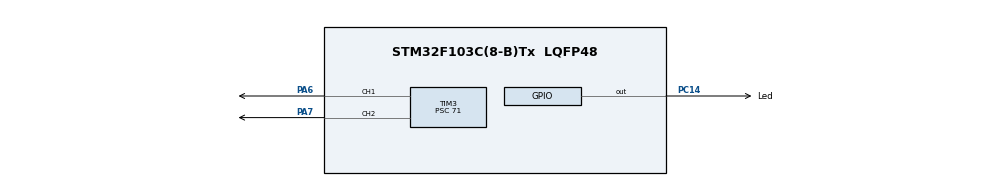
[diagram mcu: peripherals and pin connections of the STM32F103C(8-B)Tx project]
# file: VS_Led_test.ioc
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Mcu.Family=STM32F1
Mcu.Name=STM32F103C(8-B)Tx
Mcu.Package=LQFP48
NVIC.PriorityGroup=NVIC_PRIORITYGROUP_4
PA13.Mode=Serial_Wire
PA13.Signal=SYS_JTMS-SWDIO
PA14.Mode=Serial_Wire
PA14.Signal=SYS_JTCK-SWCLK
PA6.Signal=S_TIM3_CH1
PA7.Signal=S_TIM3_CH2
PC14-OSC32_IN.GPIO_Label=Led
PC14-OSC32_IN.PinState=GPIO_PIN_SET
PC14-OSC32_IN.Signal=GPIO_Output
PD0-OSC_IN.Mode=HSE-External-Oscillator
PD0-OSC_IN.Signal=RCC_OSC_IN
PD1-OSC_OUT.Mode=HSE-External-Oscillator
PD1-OSC_OUT.Signal=RCC_OSC_OUT
ProjectManager.HeapSize=0x200
ProjectManager.StackSize=0x400
ProjectManager.TargetToolchain=CMake
RCC.APB1Freq_Value=8000000
RCC.APB2Freq_Value=8000000
SH.S_TIM3_CH1.0=TIM3_CH1,PWM Generation1 CH1
SH.S_TIM3_CH2.0=TIM3_CH2,PWM Generation2 CH2
TIM3.AutoReloadPreload=TIM_AUTORELOAD_PRELOAD_ENABLE
TIM3.Channel-PWM\ Generation1\ CH1=TIM_CHANNEL_1
TIM3.Channel-PWM\ Generation2\ CH2=TIM_CHANNEL_2
TIM3.Period=999
TIM3.Prescaler=71
VP_TIM3_VS_ClockSourceINT.Mode=Internal
board=custom

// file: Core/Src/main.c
/* USER CODE BEGIN Header */
/**
  ******************************************************************************
  * @file           : main.c
  * @brief          : Main program body
  ******************************************************************************
  * @attention
  *
  * Copyright (c) 2026 STMicroelectronics.
  * All rights reserved.
  *
  * This software is licensed under terms that can be found in the LICENSE file
  * in the root directory of this software component.
  * If no LICENSE file comes with this software, it is provided AS-IS.
  *
  ******************************************************************************
  */
/* USER CODE END Header */
#include "main.h"

/* USER CODE BEGIN Includes */
#include "Trace.h"
#include "Motor.h"
#include "PID.h"
/* USER CODE END Includes */

/* USER CODE BEGIN PD */
#define TRACE_LOST_STOP_MS   500U
#define SEARCH_RAMP_MS       150U
#define STARTUP_SETTLE_MS    200U

/* USER CODE END PD */

TIM_HandleTypeDef htim3;

/* USER CODE BEGIN PV */
static uint32_t trace_lost_since = 0U;
static uint8_t startup_done = 0U;

/* USER CODE END PV */

void SystemClock_Config(void);
static void MX_GPIO_Init(void);
static void MX_TIM3_Init(void);

/* USER CODE BEGIN 0 */
static float absf_local(float value)
{
  return (value < 0.0f) ? -value : value;
}

static int16_t clamp_i16(int16_t value, int16_t min_value, int16_t max_value)
{
  if (value < min_value)
  {
    return min_value;
  }
  if (value > max_value)
  {
    return max_value;
  }
  return value;
}

/* USER CODE END 0 */

int main(void)
{

  /* MCU Configuration--------------------------------------------------------*/

  /* Reset of all peripherals, Initializes the Flash interface and the Systick. */
  HAL_Init();

  /* Configure the system clock */
  SystemClock_Config();

  /* Initialize all configured peripherals */
  MX_GPIO_Init();
  MX_TIM3_Init();
  /* USER CODE BEGIN 2 */

  HAL_TIM_PWM_Start(&htim3, TIM_CHANNEL_1);
  HAL_TIM_PWM_Start(&htim3, TIM_CHANNEL_2);

  // 启动稳定期：让传感器滤波器建立稳态
  {
    uint32_t settle_start = HAL_GetTick();
    while ((HAL_GetTick() - settle_start) < STARTUP_SETTLE_MS) {
      trace_get_error();
      HAL_Delay(10);
    }
    startup_done = 1U;
    pid_reset();
  }

  /* USER CODE END 2 */

  /* Infinite loop */
  /* USER CODE BEGIN WHILE */
  while (1)
  {
    float error = trace_get_error();
    const TraceState *trace = trace_get_state();
    uint8_t line_lost = trace->line_lost;

    if (line_lost)
    {
      float last_err = trace_get_last_error();
      uint32_t now = HAL_GetTick();

      if (trace_lost_since == 0U)
      {
        trace_lost_since = now;
      }

      uint32_t lost_duration = now - trace_lost_since;

      if (lost_duration >= TRACE_LOST_STOP_MS)
      {
        motor_stop();
        pid_reset();
        HAL_Delay(10);
        continue;
      }

      // 渐进式搜索：速度随丢线时间增加
      int16_t search_spd = (int16_t)(SEARCH_SPEED / 2);
      if (lost_duration > SEARCH_RAMP_MS)
      {
        search_spd = SEARCH_SPEED;
      }

      if (last_err >= 0.0f)
      {
        motor_set(search_spd, -search_spd);
      }
      else
      {
        motor_set(-search_spd, search_spd);
      }
      HAL_Delay(10);
      continue;
    }

    trace_lost_since = 0U;
    calc_pid(error, line_lost);

    float abs_error = absf_local(error);
    int16_t base_speed = (int16_t)(BASE_SPEED - (int16_t)(abs_error * TURN_SLOWDOWN));

    if (trace->wide)
    {
      base_speed = CROSS_SPEED;
    }
    else if ((trace->count >= 3U) && (abs_error < 1.5f))
    {
      base_speed = MIN_RUN_SPEED;
    }
    else if (abs_error < 0.6f)
    {
      base_speed = MAX_RUN_SPEED;
    }

    if (base_speed < MIN_RUN_SPEED)
    {
      base_speed = MIN_RUN_SPEED;
    }
    if (base_speed > MAX_RUN_SPEED)
    {
      base_speed = MAX_RUN_SPEED;
    }

    float pid_out = get_pid_output();
    int16_t left  = (int16_t)(base_speed + (int16_t)pid_out);
    int16_t right = (int16_t)(base_speed - (int16_t)pid_out);

    // 大误差时允许内侧轮反转实现原地转弯
    int16_t reverse_limit = (abs_error > 3.0f) ? (int16_t)(-SEARCH_SPEED) : 0;
    left  = clamp_i16(left,  reverse_limit, PWM_MAX);
    right = clamp_i16(right, reverse_limit, PWM_MAX);

    motor_set(left, right);

    HAL_Delay(10);
    /* USER CODE END WHILE */

  }
}

void SystemClock_Config(void)
{
  RCC_OscInitTypeDef RCC_OscInitStruct = {0};
  RCC_ClkInitTypeDef RCC_ClkInitStruct = {0};

  /** Initializes the RCC Oscillators according to the specified parameters
  * in the RCC_OscInitTypeDef structure.
  */
  RCC_OscInitStruct.OscillatorType = RCC_OSCILLATORTYPE_HSE;
  RCC_OscInitStruct.HSEState = RCC_HSE_ON;
  RCC_OscInitStruct.HSEPredivValue = RCC_HSE_PREDIV_DIV1;
  RCC_OscInitStruct.PLL.PLLState = RCC_PLL_ON;
  RCC_OscInitStruct.PLL.PLLSource = RCC_PLLSOURCE_HSE;
  RCC_OscInitStruct.PLL.PLLMUL = RCC_PLL_MUL9;
  if (HAL_RCC_OscConfig(&RCC_OscInitStruct) != HAL_OK)
  {
    Error_Handler();
  }

  /** Initializes the CPU, AHB and APB buses clocks
  */
  RCC_ClkInitStruct.ClockType = RCC_CLOCKTYPE_HCLK|RCC_CLOCKTYPE_SYSCLK
                              |RCC_CLOCKTYPE_PCLK1|RCC_CLOCKTYPE_PCLK2;
  RCC_ClkInitStruct.SYSCLKSource = RCC_SYSCLKSOURCE_PLLCLK;
  RCC_ClkInitStruct.AHBCLKDivider = RCC_SYSCLK_DIV1;
  RCC_ClkInitStruct.APB1CLKDivider = RCC_HCLK_DIV2;
  RCC_ClkInitStruct.APB2CLKDivider = RCC_HCLK_DIV1;

  if (HAL_RCC_ClockConfig(&RCC_ClkInitStruct, FLASH_LATENCY_2) != HAL_OK)
  {
    Error_Handler();
  }
}

static void MX_TIM3_Init(void)
{

  TIM_ClockConfigTypeDef sClockSourceConfig = {0};
  TIM_MasterConfigTypeDef sMasterConfig = {0};
  TIM_OC_InitTypeDef sConfigOC = {0};

  htim3.Instance = TIM3;
  htim3.Init.Prescaler = 71;
  htim3.Init.CounterMode = TIM_COUNTERMODE_UP;
  htim3.Init.Period = 999;
  htim3.Init.ClockDivision = TIM_CLOCKDIVISION_DIV1;
  htim3.Init.AutoReloadPreload = TIM_AUTORELOAD_PRELOAD_ENABLE;
  if (HAL_TIM_Base_Init(&htim3) != HAL_OK)
  {
    Error_Handler();
  }
  sClockSourceConfig.ClockSource = TIM_CLOCKSOURCE_INTERNAL;
  if (HAL_TIM_ConfigClockSource(&htim3, &sClockSourceConfig) != HAL_OK)
  {
    Error_Handler();
  }
  if (HAL_TIM_PWM_Init(&htim3) != HAL_OK)
  {
    Error_Handler();
  }
  sMasterConfig.MasterOutputTrigger = TIM_TRGO_RESET;
  sMasterConfig.MasterSlaveMode = TIM_MASTERSLAVEMODE_DISABLE;
  if (HAL_TIMEx_MasterConfigSynchronization(&htim3, &sMasterConfig) != HAL_OK)
  {
    Error_Handler();
  }
  sConfigOC.OCMode = TIM_OCMODE_PWM1;
  sConfigOC.Pulse = 0;
  sConfigOC.OCPolarity = TIM_OCPOLARITY_HIGH;
  sConfigOC.OCFastMode = TIM_OCFAST_DISABLE;
  if (HAL_TIM_PWM_ConfigChannel(&htim3, &sConfigOC, TIM_CHANNEL_1) != HAL_OK)
  {
    Error_Handler();
  }
  if (HAL_TIM_PWM_ConfigChannel(&htim3, &sConfigOC, TIM_CHANNEL_2) != HAL_OK)
  {
    Error_Handler();
  }
  HAL_TIM_MspPostInit(&htim3);

}

static void MX_GPIO_Init(void)
{
  GPIO_InitTypeDef GPIO_InitStruct = {0};

  /* GPIO Ports Clock Enable */
  __HAL_RCC_GPIOC_CLK_ENABLE();
  __HAL_RCC_GPIOD_CLK_ENABLE();
  __HAL_RCC_GPIOA_CLK_ENABLE();
  __HAL_RCC_GPIOB_CLK_ENABLE();
  __HAL_RCC_AFIO_CLK_ENABLE();

  /*Configure GPIO pin Output Level */
  HAL_GPIO_WritePin(Led_GPIO_Port, Led_Pin, GPIO_PIN_SET);

  /*Configure GPIO pin : Led_Pin */
  GPIO_InitStruct.Pin = Led_Pin;
  GPIO_InitStruct.Mode = GPIO_MODE_OUTPUT_PP;
  GPIO_InitStruct.Pull = GPIO_NOPULL;
  GPIO_InitStruct.Speed = GPIO_SPEED_FREQ_LOW;
  HAL_GPIO_Init(Led_GPIO_Port, &GPIO_InitStruct);

  /* USER CODE BEGIN MX_GPIO_Init_2 */

  // --- 循迹传感器输入 (PA8, PA9) ---
  GPIO_InitStruct.Pin = S5_PIN | S6_PIN;
  GPIO_InitStruct.Mode = GPIO_MODE_INPUT;
  GPIO_InitStruct.Pull = GPIO_PULLUP;
  HAL_GPIO_Init(GPIOA, &GPIO_InitStruct);

  // --- 循迹传感器输入 (PB12-PB15) ---
  GPIO_InitStruct.Pin = S1_PIN | S2_PIN | S3_PIN | S4_PIN;
  GPIO_InitStruct.Mode = GPIO_MODE_INPUT;
  GPIO_InitStruct.Pull = GPIO_PULLUP;
  HAL_GPIO_Init(GPIOB, &GPIO_InitStruct);

  // --- 电机方向控制输出 (PB0, PB1, PB10, PB11) ---
  GPIO_InitStruct.Pin = MOTOR_L_IN1_PIN | MOTOR_L_IN2_PIN |
                        MOTOR_R_IN1_PIN | MOTOR_R_IN2_PIN;
  GPIO_InitStruct.Mode = GPIO_MODE_OUTPUT_PP;
  GPIO_InitStruct.Pull = GPIO_NOPULL;
  GPIO_InitStruct.Speed = GPIO_SPEED_FREQ_LOW;
  HAL_GPIO_Init(GPIOB, &GPIO_InitStruct);

  /* USER CODE END MX_GPIO_Init_2 */
}

void Error_Handler(void)
{
  __disable_irq();
  while (1)
  {
  }
}
